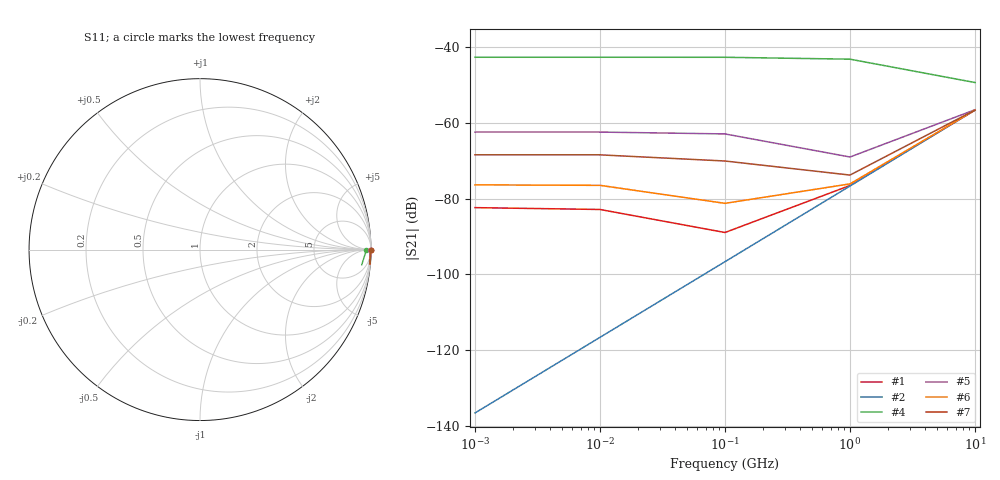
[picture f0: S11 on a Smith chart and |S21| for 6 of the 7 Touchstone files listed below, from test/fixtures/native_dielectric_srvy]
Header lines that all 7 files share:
! Sonnet Data File
! From: em Version : 18.53-Lite
! Data is NOT De-embedded
# GHZ S RI R 50.00000
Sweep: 1 MHz to 10 GHz
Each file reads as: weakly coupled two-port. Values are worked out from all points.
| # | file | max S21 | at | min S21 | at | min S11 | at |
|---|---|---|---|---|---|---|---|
| 1 | aniso_fields.native.s2p | -56.56 dB | 10 GHz | -88.9 dB | 100 MHz | 0.0 dB | 10 GHz |
| 2 | bare_seven.native.s2p | -56.56 dB | 10 GHz | -136.6 dB | 1 MHz | 0.0 dB | 10 GHz |
| 3 | base.native.s2p | -56.56 dB | 10 GHz | -136.6 dB | 1 MHz | 0.0 dB | 10 GHz |
| 4 | first_cdvy_srvy.native.s2p | -42.58 dB | 1 MHz | -49.3 dB | 10 GHz | -0.4 dB | 10 GHz |
| 5 | sigma_0p1.native.s2p | -56.45 dB | 10 GHz | -69.0 dB | 1 GHz | 0.0 dB | 10 GHz |
| 6 | sigma_0p02.native.s2p | -56.56 dB | 10 GHz | -81.2 dB | 100 MHz | 0.0 dB | 10 GHz |
| 7 | sigma_0p05.native.s2p | -56.54 dB | 10 GHz | -73.7 dB | 1 GHz | 0.0 dB | 10 GHz |
